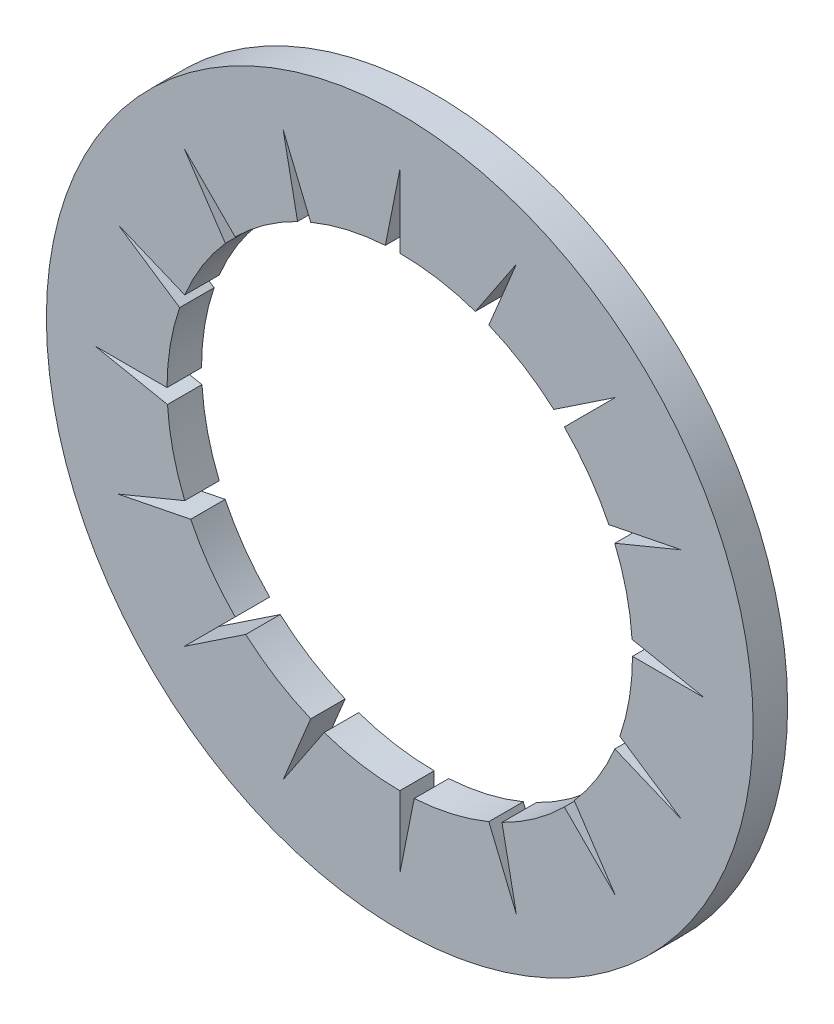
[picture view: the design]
ISO-10303-21;
HEADER;
FILE_DESCRIPTION(('STEP AP214'),'2;1');
FILE_NAME('part.step','',(''),(''),'','','');
FILE_SCHEMA(('AUTOMOTIVE_DESIGN { 1 0 10303 214 1 1 1 1 }'));
ENDSEC;
DATA;
#1=APPLICATION_CONTEXT('core data for automotive mechanical design processes');
#2=APPLICATION_PROTOCOL_DEFINITION('international standard','automotive_design',2000,#1);
#3=PRODUCT_CONTEXT('',#1,'mechanical');
#4=PRODUCT('Part','Part','',(#3));
#5=PRODUCT_RELATED_PRODUCT_CATEGORY('part','',(#4));
#6=PRODUCT_DEFINITION_FORMATION('','',#4);
#7=PRODUCT_DEFINITION_CONTEXT('part definition',#1,'design');
#8=PRODUCT_DEFINITION('design','',#6,#7);
#9=PRODUCT_DEFINITION_SHAPE('','',#8);
#10=(LENGTH_UNIT() NAMED_UNIT(*) SI_UNIT(.MILLI.,.METRE.));
#11=(NAMED_UNIT(*) PLANE_ANGLE_UNIT() SI_UNIT($,.RADIAN.));
#12=(NAMED_UNIT(*) SI_UNIT($,.STERADIAN.) SOLID_ANGLE_UNIT());
#13=UNCERTAINTY_MEASURE_WITH_UNIT(LENGTH_MEASURE(1.E-05),#10,'distance_accuracy_value','');
#14=(GEOMETRIC_REPRESENTATION_CONTEXT(3) GLOBAL_UNCERTAINTY_ASSIGNED_CONTEXT((#13)) GLOBAL_UNIT_ASSIGNED_CONTEXT((#10,
#11,#12)) REPRESENTATION_CONTEXT('',''));
#15=CARTESIAN_POINT('',(0.,0.,0.));
#16=DIRECTION('',(0.,0.,1.));
#17=DIRECTION('',(1.,0.,0.));
#18=AXIS2_PLACEMENT_3D('',#15,#16,#17);
#19=CARTESIAN_POINT('',(0.,0.,0.));
#20=DIRECTION('',(0.,0.,1.));
#21=DIRECTION('',(1.,0.,0.));
#22=AXIS2_PLACEMENT_3D('',#19,#20,#21);
#23=CYLINDRICAL_SURFACE('',#22,6.75);
#24=DIRECTION('',(0.,0.,1.));
#25=VECTOR('',#24,1.);
#26=CARTESIAN_POINT('',(-2.58311316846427,6.23618684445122,-1.));
#27=LINE('',#26,#25);
#28=CARTESIAN_POINT('',(-2.58311316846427,6.23618684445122,-1.));
#29=VERTEX_POINT('',#28);
#30=CARTESIAN_POINT('',(-2.58311316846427,6.23618684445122,0.));
#31=VERTEX_POINT('',#30);
#32=EDGE_CURVE('E371',#29,#31,#27,.T.);
#33=ORIENTED_EDGE('',*,*,#32,.F.);
#34=CARTESIAN_POINT('',(0.,0.,-1.));
#35=DIRECTION('',(0.,0.,1.));
#36=DIRECTION('',(1.,0.,0.));
#37=AXIS2_PLACEMENT_3D('',#34,#35,#36);
#38=CIRCLE('',#37,6.75);
#39=CARTESIAN_POINT('',(-0.418307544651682,6.73702596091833,-1.));
#40=VERTEX_POINT('',#39);
#41=EDGE_CURVE('E11',#40,#29,#38,.T.);
#42=ORIENTED_EDGE('',*,*,#41,.F.);
#43=DIRECTION('',(0.,0.,1.));
#44=VECTOR('',#43,1.);
#45=CARTESIAN_POINT('',(-0.418307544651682,6.73702596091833,-1.));
#46=LINE('',#45,#44);
#47=CARTESIAN_POINT('',(-0.418307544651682,6.73702596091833,0.));
#48=VERTEX_POINT('',#47);
#49=EDGE_CURVE('E651',#40,#48,#46,.T.);
#50=ORIENTED_EDGE('',*,*,#49,.T.);
#51=CARTESIAN_POINT('',(0.,0.,0.));
#52=DIRECTION('',(0.,0.,1.));
#53=DIRECTION('',(1.,0.,0.));
#54=AXIS2_PLACEMENT_3D('',#51,#52,#53);
#55=CIRCLE('',#54,6.75);
#56=EDGE_CURVE('E656',#48,#31,#55,.T.);
#57=ORIENTED_EDGE('',*,*,#56,.T.);
#58=EDGE_LOOP('',(#33,#42,#50,#57));
#59=FACE_BOUND('',#58,.T.);
#60=ADVANCED_FACE('F41',(#59),#23,.F.);
#61=DIRECTION('',(0.,0.,1.));
#62=VECTOR('',#61,1.);
#63=CARTESIAN_POINT('',(-2.9646139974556,6.06412102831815,-1.));
#64=LINE('',#63,#62);
#65=CARTESIAN_POINT('',(-2.9646139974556,6.06412102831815,-1.));
#66=VERTEX_POINT('',#65);
#67=CARTESIAN_POINT('',(-2.9646139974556,6.06412102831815,0.));
#68=VERTEX_POINT('',#67);
#69=EDGE_CURVE('E353',#66,#68,#64,.T.);
#70=ORIENTED_EDGE('',*,*,#69,.T.);
#71=CARTESIAN_POINT('',(-4.77297077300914,4.77297077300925,0.));
#72=VERTEX_POINT('',#71);
#73=EDGE_CURVE('E660',#68,#72,#55,.T.);
#74=ORIENTED_EDGE('',*,*,#73,.T.);
#75=DIRECTION('',(0.,0.,1.));
#76=VECTOR('',#75,1.);
#77=CARTESIAN_POINT('',(-4.77297077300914,4.77297077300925,-1.));
#78=LINE('',#77,#76);
#79=CARTESIAN_POINT('',(-4.77297077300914,4.77297077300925,-1.));
#80=VERTEX_POINT('',#79);
#81=EDGE_CURVE('E384',#80,#72,#78,.T.);
#82=ORIENTED_EDGE('',*,*,#81,.F.);
#83=EDGE_CURVE('E49',#66,#80,#38,.T.);
#84=ORIENTED_EDGE('',*,*,#83,.F.);
#85=EDGE_LOOP('',(#70,#74,#82,#84));
#86=FACE_BOUND('',#85,.T.);
#87=ADVANCED_FACE('F712',(#86),#23,.F.);
#88=DIRECTION('',(0.,0.,1.));
#89=VECTOR('',#88,1.);
#90=CARTESIAN_POINT('',(-5.05958484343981,4.46800864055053,-1.));
#91=LINE('',#90,#89);
#92=CARTESIAN_POINT('',(-5.05958484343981,4.46800864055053,-1.));
#93=VERTEX_POINT('',#92);
#94=CARTESIAN_POINT('',(-5.05958484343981,4.46800864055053,0.));
#95=VERTEX_POINT('',#94);
#96=EDGE_CURVE('E387',#93,#95,#91,.T.);
#97=ORIENTED_EDGE('',*,*,#96,.T.);
#98=CARTESIAN_POINT('',(-6.23618684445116,2.58311316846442,0.));
#99=VERTEX_POINT('',#98);
#100=EDGE_CURVE('E715',#95,#99,#55,.T.);
#101=ORIENTED_EDGE('',*,*,#100,.T.);
#102=DIRECTION('',(0.,0.,1.));
#103=VECTOR('',#102,1.);
#104=CARTESIAN_POINT('',(-6.23618684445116,2.58311316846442,-1.));
#105=LINE('',#104,#103);
#106=CARTESIAN_POINT('',(-6.23618684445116,2.58311316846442,-1.));
#107=VERTEX_POINT('',#106);
#108=EDGE_CURVE('E401',#107,#99,#105,.T.);
#109=ORIENTED_EDGE('',*,*,#108,.F.);
#110=EDGE_CURVE('E702',#93,#107,#38,.T.);
#111=ORIENTED_EDGE('',*,*,#110,.F.);
#112=EDGE_LOOP('',(#97,#101,#109,#111));
#113=FACE_BOUND('',#112,.T.);
#114=ADVANCED_FACE('F787',(#113),#23,.F.);
#115=DIRECTION('',(0.,0.,1.));
#116=VECTOR('',#115,1.);
#117=CARTESIAN_POINT('',(-6.38427976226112,2.19168243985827,-1.));
#118=LINE('',#117,#116);
#119=CARTESIAN_POINT('',(-6.38427976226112,2.19168243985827,-1.));
#120=VERTEX_POINT('',#119);
#121=CARTESIAN_POINT('',(-6.38427976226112,2.19168243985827,0.));
#122=VERTEX_POINT('',#121);
#123=EDGE_CURVE('E405',#120,#122,#118,.T.);
#124=ORIENTED_EDGE('',*,*,#123,.T.);
#125=CARTESIAN_POINT('',(-6.75,0.,0.));
#126=VERTEX_POINT('',#125);
#127=EDGE_CURVE('E716',#122,#126,#55,.T.);
#128=ORIENTED_EDGE('',*,*,#127,.T.);
#129=DIRECTION('',(0.,0.,1.));
#130=VECTOR('',#129,1.);
#131=CARTESIAN_POINT('',(-6.75,0.,-1.));
#132=LINE('',#131,#130);
#133=CARTESIAN_POINT('',(-6.75,0.,-1.));
#134=VERTEX_POINT('',#133);
#135=EDGE_CURVE('E420',#134,#126,#132,.T.);
#136=ORIENTED_EDGE('',*,*,#135,.F.);
#137=EDGE_CURVE('E699',#120,#134,#38,.T.);
#138=ORIENTED_EDGE('',*,*,#137,.F.);
#139=EDGE_LOOP('',(#124,#128,#136,#138));
#140=FACE_BOUND('',#139,.T.);
#141=ADVANCED_FACE('F927',(#140),#23,.F.);
#142=DIRECTION('',(0.,0.,1.));
#143=VECTOR('',#142,1.);
#144=CARTESIAN_POINT('',(-6.73702596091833,-0.418307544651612,-1.));
#145=LINE('',#144,#143);
#146=CARTESIAN_POINT('',(-6.73702596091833,-0.418307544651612,-1.));
#147=VERTEX_POINT('',#146);
#148=CARTESIAN_POINT('',(-6.73702596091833,-0.418307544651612,0.));
#149=VERTEX_POINT('',#148);
#150=EDGE_CURVE('E424',#147,#149,#145,.T.);
#151=ORIENTED_EDGE('',*,*,#150,.T.);
#152=CARTESIAN_POINT('',(-6.23618684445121,-2.58311316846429,0.));
#153=VERTEX_POINT('',#152);
#154=EDGE_CURVE('E720',#149,#153,#55,.T.);
#155=ORIENTED_EDGE('',*,*,#154,.T.);
#156=DIRECTION('',(0.,0.,1.));
#157=VECTOR('',#156,1.);
#158=CARTESIAN_POINT('',(-6.23618684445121,-2.58311316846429,-1.));
#159=LINE('',#158,#157);
#160=CARTESIAN_POINT('',(-6.23618684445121,-2.58311316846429,-1.));
#161=VERTEX_POINT('',#160);
#162=EDGE_CURVE('E439',#161,#153,#159,.T.);
#163=ORIENTED_EDGE('',*,*,#162,.F.);
#164=EDGE_CURVE('E696',#147,#161,#38,.T.);
#165=ORIENTED_EDGE('',*,*,#164,.F.);
#166=EDGE_LOOP('',(#151,#155,#163,#165));
#167=FACE_BOUND('',#166,.T.);
#168=ADVANCED_FACE('F919',(#167),#23,.F.);
#169=DIRECTION('',(0.,0.,1.));
#170=VECTOR('',#169,1.);
#171=CARTESIAN_POINT('',(-6.06412102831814,-2.96461399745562,-1.));
#172=LINE('',#171,#170);
#173=CARTESIAN_POINT('',(-6.06412102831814,-2.96461399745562,-1.));
#174=VERTEX_POINT('',#173);
#175=CARTESIAN_POINT('',(-6.06412102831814,-2.96461399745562,0.));
#176=VERTEX_POINT('',#175);
#177=EDGE_CURVE('E443',#174,#176,#172,.T.);
#178=ORIENTED_EDGE('',*,*,#177,.T.);
#179=CARTESIAN_POINT('',(-4.77297077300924,-4.77297077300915,0.));
#180=VERTEX_POINT('',#179);
#181=EDGE_CURVE('E724',#176,#180,#55,.T.);
#182=ORIENTED_EDGE('',*,*,#181,.T.);
#183=DIRECTION('',(0.,0.,1.));
#184=VECTOR('',#183,1.);
#185=CARTESIAN_POINT('',(-4.77297077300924,-4.77297077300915,-1.));
#186=LINE('',#185,#184);
#187=CARTESIAN_POINT('',(-4.77297077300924,-4.77297077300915,-1.));
#188=VERTEX_POINT('',#187);
#189=EDGE_CURVE('E458',#188,#180,#186,.T.);
#190=ORIENTED_EDGE('',*,*,#189,.F.);
#191=EDGE_CURVE('E693',#174,#188,#38,.T.);
#192=ORIENTED_EDGE('',*,*,#191,.F.);
#193=EDGE_LOOP('',(#178,#182,#190,#192));
#194=FACE_BOUND('',#193,.T.);
#195=ADVANCED_FACE('F912',(#194),#23,.F.);
#196=DIRECTION('',(0.,0.,1.));
#197=VECTOR('',#196,1.);
#198=CARTESIAN_POINT('',(-4.46800864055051,-5.05958484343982,-1.));
#199=LINE('',#198,#197);
#200=CARTESIAN_POINT('',(-4.46800864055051,-5.05958484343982,-1.));
#201=VERTEX_POINT('',#200);
#202=CARTESIAN_POINT('',(-4.46800864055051,-5.05958484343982,0.));
#203=VERTEX_POINT('',#202);
#204=EDGE_CURVE('E462',#201,#203,#199,.T.);
#205=ORIENTED_EDGE('',*,*,#204,.T.);
#206=CARTESIAN_POINT('',(-2.58311316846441,-6.23618684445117,0.));
#207=VERTEX_POINT('',#206);
#208=EDGE_CURVE('E728',#203,#207,#55,.T.);
#209=ORIENTED_EDGE('',*,*,#208,.T.);
#210=DIRECTION('',(0.,0.,1.));
#211=VECTOR('',#210,1.);
#212=CARTESIAN_POINT('',(-2.58311316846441,-6.23618684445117,-1.));
#213=LINE('',#212,#211);
#214=CARTESIAN_POINT('',(-2.58311316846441,-6.23618684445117,-1.));
#215=VERTEX_POINT('',#214);
#216=EDGE_CURVE('E477',#215,#207,#213,.T.);
#217=ORIENTED_EDGE('',*,*,#216,.F.);
#218=EDGE_CURVE('E690',#201,#215,#38,.T.);
#219=ORIENTED_EDGE('',*,*,#218,.F.);
#220=EDGE_LOOP('',(#205,#209,#217,#219));
#221=FACE_BOUND('',#220,.T.);
#222=ADVANCED_FACE('F904',(#221),#23,.F.);
#223=DIRECTION('',(0.,0.,1.));
#224=VECTOR('',#223,1.);
#225=CARTESIAN_POINT('',(-2.19168243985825,-6.38427976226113,-1.));
#226=LINE('',#225,#224);
#227=CARTESIAN_POINT('',(-2.19168243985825,-6.38427976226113,-1.));
#228=VERTEX_POINT('',#227);
#229=CARTESIAN_POINT('',(-2.19168243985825,-6.38427976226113,0.));
#230=VERTEX_POINT('',#229);
#231=EDGE_CURVE('E481',#228,#230,#226,.T.);
#232=ORIENTED_EDGE('',*,*,#231,.T.);
#233=CARTESIAN_POINT('',(0.,-6.75,0.));
#234=VERTEX_POINT('',#233);
#235=EDGE_CURVE('E732',#230,#234,#55,.T.);
#236=ORIENTED_EDGE('',*,*,#235,.T.);
#237=DIRECTION('',(0.,0.,1.));
#238=VECTOR('',#237,1.);
#239=CARTESIAN_POINT('',(0.,-6.75,-1.));
#240=LINE('',#239,#238);
#241=CARTESIAN_POINT('',(0.,-6.75,-1.));
#242=VERTEX_POINT('',#241);
#243=EDGE_CURVE('E496',#242,#234,#240,.T.);
#244=ORIENTED_EDGE('',*,*,#243,.F.);
#245=EDGE_CURVE('E687',#228,#242,#38,.T.);
#246=ORIENTED_EDGE('',*,*,#245,.F.);
#247=EDGE_LOOP('',(#232,#236,#244,#246));
#248=FACE_BOUND('',#247,.T.);
#249=ADVANCED_FACE('F897',(#248),#23,.F.);
#250=DIRECTION('',(0.,0.,1.));
#251=VECTOR('',#250,1.);
#252=CARTESIAN_POINT('',(0.418307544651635,-6.73702596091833,-1.));
#253=LINE('',#252,#251);
#254=CARTESIAN_POINT('',(0.418307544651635,-6.73702596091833,-1.));
#255=VERTEX_POINT('',#254);
#256=CARTESIAN_POINT('',(0.418307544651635,-6.73702596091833,0.));
#257=VERTEX_POINT('',#256);
#258=EDGE_CURVE('E500',#255,#257,#253,.T.);
#259=ORIENTED_EDGE('',*,*,#258,.T.);
#260=CARTESIAN_POINT('',(2.58311316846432,-6.2361868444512,0.));
#261=VERTEX_POINT('',#260);
#262=EDGE_CURVE('E736',#257,#261,#55,.T.);
#263=ORIENTED_EDGE('',*,*,#262,.T.);
#264=DIRECTION('',(0.,0.,1.));
#265=VECTOR('',#264,1.);
#266=CARTESIAN_POINT('',(2.58311316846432,-6.2361868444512,-1.));
#267=LINE('',#266,#265);
#268=CARTESIAN_POINT('',(2.58311316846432,-6.2361868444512,-1.));
#269=VERTEX_POINT('',#268);
#270=EDGE_CURVE('E515',#269,#261,#267,.T.);
#271=ORIENTED_EDGE('',*,*,#270,.F.);
#272=EDGE_CURVE('E684',#255,#269,#38,.T.);
#273=ORIENTED_EDGE('',*,*,#272,.F.);
#274=EDGE_LOOP('',(#259,#263,#271,#273));
#275=FACE_BOUND('',#274,.T.);
#276=ADVANCED_FACE('F889',(#275),#23,.F.);
#277=DIRECTION('',(0.,0.,1.));
#278=VECTOR('',#277,1.);
#279=CARTESIAN_POINT('',(2.96461399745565,-6.06412102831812,-1.));
#280=LINE('',#279,#278);
#281=CARTESIAN_POINT('',(2.96461399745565,-6.06412102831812,-1.));
#282=VERTEX_POINT('',#281);
#283=CARTESIAN_POINT('',(2.96461399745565,-6.06412102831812,0.));
#284=VERTEX_POINT('',#283);
#285=EDGE_CURVE('E519',#282,#284,#280,.T.);
#286=ORIENTED_EDGE('',*,*,#285,.T.);
#287=CARTESIAN_POINT('',(4.77297077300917,-4.77297077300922,0.));
#288=VERTEX_POINT('',#287);
#289=EDGE_CURVE('E740',#284,#288,#55,.T.);
#290=ORIENTED_EDGE('',*,*,#289,.T.);
#291=DIRECTION('',(0.,0.,1.));
#292=VECTOR('',#291,1.);
#293=CARTESIAN_POINT('',(4.77297077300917,-4.77297077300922,-1.));
#294=LINE('',#293,#292);
#295=CARTESIAN_POINT('',(4.77297077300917,-4.77297077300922,-1.));
#296=VERTEX_POINT('',#295);
#297=EDGE_CURVE('E534',#296,#288,#294,.T.);
#298=ORIENTED_EDGE('',*,*,#297,.F.);
#299=EDGE_CURVE('E681',#282,#296,#38,.T.);
#300=ORIENTED_EDGE('',*,*,#299,.F.);
#301=EDGE_LOOP('',(#286,#290,#298,#300));
#302=FACE_BOUND('',#301,.T.);
#303=ADVANCED_FACE('F882',(#302),#23,.F.);
#304=DIRECTION('',(0.,0.,1.));
#305=VECTOR('',#304,1.);
#306=CARTESIAN_POINT('',(5.05958484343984,-4.46800864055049,-1.));
#307=LINE('',#306,#305);
#308=CARTESIAN_POINT('',(5.05958484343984,-4.46800864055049,-1.));
#309=VERTEX_POINT('',#308);
#310=CARTESIAN_POINT('',(5.05958484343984,-4.46800864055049,0.));
#311=VERTEX_POINT('',#310);
#312=EDGE_CURVE('E538',#309,#311,#307,.T.);
#313=ORIENTED_EDGE('',*,*,#312,.T.);
#314=CARTESIAN_POINT('',(6.23618684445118,-2.58311316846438,0.));
#315=VERTEX_POINT('',#314);
#316=EDGE_CURVE('E744',#311,#315,#55,.T.);
#317=ORIENTED_EDGE('',*,*,#316,.T.);
#318=DIRECTION('',(0.,0.,1.));
#319=VECTOR('',#318,1.);
#320=CARTESIAN_POINT('',(6.23618684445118,-2.58311316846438,-1.));
#321=LINE('',#320,#319);
#322=CARTESIAN_POINT('',(6.23618684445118,-2.58311316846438,-1.));
#323=VERTEX_POINT('',#322);
#324=EDGE_CURVE('E553',#323,#315,#321,.T.);
#325=ORIENTED_EDGE('',*,*,#324,.F.);
#326=EDGE_CURVE('E678',#309,#323,#38,.T.);
#327=ORIENTED_EDGE('',*,*,#326,.F.);
#328=EDGE_LOOP('',(#313,#317,#325,#327));
#329=FACE_BOUND('',#328,.T.);
#330=ADVANCED_FACE('F874',(#329),#23,.F.);
#331=DIRECTION('',(0.,0.,1.));
#332=VECTOR('',#331,1.);
#333=CARTESIAN_POINT('',(6.38427976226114,-2.19168243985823,-1.));
#334=LINE('',#333,#332);
#335=CARTESIAN_POINT('',(6.38427976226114,-2.19168243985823,-1.));
#336=VERTEX_POINT('',#335);
#337=CARTESIAN_POINT('',(6.38427976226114,-2.19168243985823,0.));
#338=VERTEX_POINT('',#337);
#339=EDGE_CURVE('E557',#336,#338,#334,.T.);
#340=ORIENTED_EDGE('',*,*,#339,.T.);
#341=CARTESIAN_POINT('',(6.75,0.,0.));
#342=VERTEX_POINT('',#341);
#343=EDGE_CURVE('E748',#338,#342,#55,.T.);
#344=ORIENTED_EDGE('',*,*,#343,.T.);
#345=DIRECTION('',(0.,0.,1.));
#346=VECTOR('',#345,1.);
#347=CARTESIAN_POINT('',(6.75,0.,-1.));
#348=LINE('',#347,#346);
#349=CARTESIAN_POINT('',(6.75,0.,-1.));
#350=VERTEX_POINT('',#349);
#351=EDGE_CURVE('E572',#350,#342,#348,.T.);
#352=ORIENTED_EDGE('',*,*,#351,.F.);
#353=EDGE_CURVE('E675',#336,#350,#38,.T.);
#354=ORIENTED_EDGE('',*,*,#353,.F.);
#355=EDGE_LOOP('',(#340,#344,#352,#354));
#356=FACE_BOUND('',#355,.T.);
#357=ADVANCED_FACE('F867',(#356),#23,.F.);
#358=DIRECTION('',(0.,0.,1.));
#359=VECTOR('',#358,1.);
#360=CARTESIAN_POINT('',(6.73702596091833,0.418307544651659,-1.));
#361=LINE('',#360,#359);
#362=CARTESIAN_POINT('',(6.73702596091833,0.418307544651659,-1.));
#363=VERTEX_POINT('',#362);
#364=CARTESIAN_POINT('',(6.73702596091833,0.418307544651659,0.));
#365=VERTEX_POINT('',#364);
#366=EDGE_CURVE('E576',#363,#365,#361,.T.);
#367=ORIENTED_EDGE('',*,*,#366,.T.);
#368=CARTESIAN_POINT('',(6.23618684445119,2.58311316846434,0.));
#369=VERTEX_POINT('',#368);
#370=EDGE_CURVE('E752',#365,#369,#55,.T.);
#371=ORIENTED_EDGE('',*,*,#370,.T.);
#372=DIRECTION('',(0.,0.,1.));
#373=VECTOR('',#372,1.);
#374=CARTESIAN_POINT('',(6.23618684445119,2.58311316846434,-1.));
#375=LINE('',#374,#373);
#376=CARTESIAN_POINT('',(6.23618684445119,2.58311316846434,-1.));
#377=VERTEX_POINT('',#376);
#378=EDGE_CURVE('E591',#377,#369,#375,.T.);
#379=ORIENTED_EDGE('',*,*,#378,.F.);
#380=EDGE_CURVE('E672',#363,#377,#38,.T.);
#381=ORIENTED_EDGE('',*,*,#380,.F.);
#382=EDGE_LOOP('',(#367,#371,#379,#381));
#383=FACE_BOUND('',#382,.T.);
#384=ADVANCED_FACE('F799',(#383),#23,.F.);
#385=DIRECTION('',(0.,0.,1.));
#386=VECTOR('',#385,1.);
#387=CARTESIAN_POINT('',(6.06412102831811,2.96461399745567,-1.));
#388=LINE('',#387,#386);
#389=CARTESIAN_POINT('',(6.06412102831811,2.96461399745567,-1.));
#390=VERTEX_POINT('',#389);
#391=CARTESIAN_POINT('',(6.06412102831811,2.96461399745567,0.));
#392=VERTEX_POINT('',#391);
#393=EDGE_CURVE('E595',#390,#392,#388,.T.);
#394=ORIENTED_EDGE('',*,*,#393,.T.);
#395=CARTESIAN_POINT('',(4.77297077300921,4.77297077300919,0.));
#396=VERTEX_POINT('',#395);
#397=EDGE_CURVE('E756',#392,#396,#55,.T.);
#398=ORIENTED_EDGE('',*,*,#397,.T.);
#399=DIRECTION('',(0.,0.,1.));
#400=VECTOR('',#399,1.);
#401=CARTESIAN_POINT('',(4.77297077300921,4.77297077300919,-1.));
#402=LINE('',#401,#400);
#403=CARTESIAN_POINT('',(4.77297077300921,4.77297077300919,-1.));
#404=VERTEX_POINT('',#403);
#405=EDGE_CURVE('E610',#404,#396,#402,.T.);
#406=ORIENTED_EDGE('',*,*,#405,.F.);
#407=EDGE_CURVE('E669',#390,#404,#38,.T.);
#408=ORIENTED_EDGE('',*,*,#407,.F.);
#409=EDGE_LOOP('',(#394,#398,#406,#408));
#410=FACE_BOUND('',#409,.T.);
#411=ADVANCED_FACE('F795',(#410),#23,.F.);
#412=DIRECTION('',(0.,0.,1.));
#413=VECTOR('',#412,1.);
#414=CARTESIAN_POINT('',(4.46800864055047,5.05958484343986,-1.));
#415=LINE('',#414,#413);
#416=CARTESIAN_POINT('',(4.46800864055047,5.05958484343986,-1.));
#417=VERTEX_POINT('',#416);
#418=CARTESIAN_POINT('',(4.46800864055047,5.05958484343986,0.));
#419=VERTEX_POINT('',#418);
#420=EDGE_CURVE('E614',#417,#419,#415,.T.);
#421=ORIENTED_EDGE('',*,*,#420,.T.);
#422=CARTESIAN_POINT('',(2.58311316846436,6.23618684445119,0.));
#423=VERTEX_POINT('',#422);
#424=EDGE_CURVE('E760',#419,#423,#55,.T.);
#425=ORIENTED_EDGE('',*,*,#424,.T.);
#426=DIRECTION('',(0.,0.,1.));
#427=VECTOR('',#426,1.);
#428=CARTESIAN_POINT('',(2.58311316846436,6.23618684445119,-1.));
#429=LINE('',#428,#427);
#430=CARTESIAN_POINT('',(2.58311316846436,6.23618684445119,-1.));
#431=VERTEX_POINT('',#430);
#432=EDGE_CURVE('E629',#431,#423,#429,.T.);
#433=ORIENTED_EDGE('',*,*,#432,.F.);
#434=EDGE_CURVE('E666',#417,#431,#38,.T.);
#435=ORIENTED_EDGE('',*,*,#434,.F.);
#436=EDGE_LOOP('',(#421,#425,#433,#435));
#437=FACE_BOUND('',#436,.T.);
#438=ADVANCED_FACE('F789',(#437),#23,.F.);
#439=DIRECTION('',(0.,0.,1.));
#440=VECTOR('',#439,1.);
#441=CARTESIAN_POINT('',(2.19168243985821,6.38427976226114,-1.));
#442=LINE('',#441,#440);
#443=CARTESIAN_POINT('',(2.19168243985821,6.38427976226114,-1.));
#444=VERTEX_POINT('',#443);
#445=CARTESIAN_POINT('',(2.19168243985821,6.38427976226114,0.));
#446=VERTEX_POINT('',#445);
#447=EDGE_CURVE('E633',#444,#446,#442,.T.);
#448=ORIENTED_EDGE('',*,*,#447,.T.);
#449=CARTESIAN_POINT('',(0.,6.75,0.));
#450=VERTEX_POINT('',#449);
#451=EDGE_CURVE('E650',#446,#450,#55,.T.);
#452=ORIENTED_EDGE('',*,*,#451,.T.);
#453=DIRECTION('',(0.,0.,1.));
#454=VECTOR('',#453,1.);
#455=CARTESIAN_POINT('',(0.,6.75,-1.));
#456=LINE('',#455,#454);
#457=CARTESIAN_POINT('',(0.,6.75,-1.));
#458=VERTEX_POINT('',#457);
#459=EDGE_CURVE('E647',#458,#450,#456,.T.);
#460=ORIENTED_EDGE('',*,*,#459,.F.);
#461=EDGE_CURVE('E50',#444,#458,#38,.T.);
#462=ORIENTED_EDGE('',*,*,#461,.F.);
#463=EDGE_LOOP('',(#448,#452,#460,#462));
#464=FACE_BOUND('',#463,.T.);
#465=ADVANCED_FACE('F43',(#464),#23,.F.);
#466=CARTESIAN_POINT('',(6.75,0.,-1.));
#467=DIRECTION('',(0.,0.,-1.));
#468=DIRECTION('',(-1.,0.,0.));
#469=AXIS2_PLACEMENT_3D('',#466,#467,#468);
#470=PLANE('',#469);
#471=DIRECTION('',(-0.382683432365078,0.923879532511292,0.));
#472=VECTOR('',#471,1.);
#473=CARTESIAN_POINT('',(-2.58311316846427,6.23618684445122,-1.));
#474=LINE('',#473,#472);
#475=CARTESIAN_POINT('',(-3.38292154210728,8.16709506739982,-1.));
#476=VERTEX_POINT('',#475);
#477=EDGE_CURVE('E349',#29,#476,#474,.T.);
#478=ORIENTED_EDGE('',*,*,#477,.T.);
#479=DIRECTION('',(0.195090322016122,-0.980785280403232,0.));
#480=VECTOR('',#479,1.);
#481=CARTESIAN_POINT('',(-3.38292154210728,8.16709506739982,-1.));
#482=LINE('',#481,#480);
#483=EDGE_CURVE('E354',#476,#66,#482,.T.);
#484=ORIENTED_EDGE('',*,*,#483,.T.);
#485=ORIENTED_EDGE('',*,*,#83,.T.);
#486=DIRECTION('',(-0.707106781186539,0.707106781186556,0.));
#487=VECTOR('',#486,1.);
#488=CARTESIAN_POINT('',(-4.77297077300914,4.77297077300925,-1.));
#489=LINE('',#488,#487);
#490=CARTESIAN_POINT('',(-6.250823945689,6.25082394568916,-1.));
#491=VERTEX_POINT('',#490);
#492=EDGE_CURVE('E374',#80,#491,#489,.T.);
#493=ORIENTED_EDGE('',*,*,#492,.T.);
#494=DIRECTION('',(0.555570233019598,-0.831469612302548,0.));
#495=VECTOR('',#494,1.);
#496=CARTESIAN_POINT('',(-6.250823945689,6.25082394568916,-1.));
#497=LINE('',#496,#495);
#498=EDGE_CURVE('E377',#491,#93,#497,.T.);
#499=ORIENTED_EDGE('',*,*,#498,.T.);
#500=ORIENTED_EDGE('',*,*,#110,.T.);
#501=DIRECTION('',(-0.923879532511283,0.3826834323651,0.));
#502=VECTOR('',#501,1.);
#503=CARTESIAN_POINT('',(-6.23618684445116,2.58311316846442,-1.));
#504=LINE('',#503,#502);
#505=CARTESIAN_POINT('',(-8.16709506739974,3.38292154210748,-1.));
#506=VERTEX_POINT('',#505);
#507=EDGE_CURVE('E391',#107,#506,#504,.T.);
#508=ORIENTED_EDGE('',*,*,#507,.T.);
#509=DIRECTION('',(0.831469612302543,-0.555570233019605,0.));
#510=VECTOR('',#509,1.);
#511=CARTESIAN_POINT('',(-8.16709506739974,3.38292154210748,-1.));
#512=LINE('',#511,#510);
#513=EDGE_CURVE('E394',#506,#120,#512,.T.);
#514=ORIENTED_EDGE('',*,*,#513,.T.);
#515=ORIENTED_EDGE('',*,*,#137,.T.);
#516=DIRECTION('',(-1.,0.,0.));
#517=VECTOR('',#516,1.);
#518=CARTESIAN_POINT('',(-6.75,0.,-1.));
#519=LINE('',#518,#517);
#520=CARTESIAN_POINT('',(-8.84,0.,-1.));
#521=VERTEX_POINT('',#520);
#522=EDGE_CURVE('E410',#134,#521,#519,.T.);
#523=ORIENTED_EDGE('',*,*,#522,.T.);
#524=DIRECTION('',(0.98078528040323,-0.195090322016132,0.));
#525=VECTOR('',#524,1.);
#526=CARTESIAN_POINT('',(-8.84,0.,-1.));
#527=LINE('',#526,#525);
#528=EDGE_CURVE('E413',#521,#147,#527,.T.);
#529=ORIENTED_EDGE('',*,*,#528,.T.);
#530=ORIENTED_EDGE('',*,*,#164,.T.);
#531=DIRECTION('',(-0.923879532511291,-0.382683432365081,0.));
#532=VECTOR('',#531,1.);
#533=CARTESIAN_POINT('',(-6.23618684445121,-2.58311316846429,-1.));
#534=LINE('',#533,#532);
#535=CARTESIAN_POINT('',(-8.16709506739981,-3.38292154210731,-1.));
#536=VERTEX_POINT('',#535);
#537=EDGE_CURVE('E429',#161,#536,#534,.T.);
#538=ORIENTED_EDGE('',*,*,#537,.T.);
#539=DIRECTION('',(0.980785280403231,0.195090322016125,0.));
#540=VECTOR('',#539,1.);
#541=CARTESIAN_POINT('',(-8.16709506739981,-3.38292154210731,-1.));
#542=LINE('',#541,#540);
#543=EDGE_CURVE('E432',#536,#174,#542,.T.);
#544=ORIENTED_EDGE('',*,*,#543,.T.);
#545=ORIENTED_EDGE('',*,*,#191,.T.);
#546=DIRECTION('',(-0.707106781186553,-0.707106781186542,0.));
#547=VECTOR('',#546,1.);
#548=CARTESIAN_POINT('',(-4.77297077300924,-4.77297077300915,-1.));
#549=LINE('',#548,#547);
#550=CARTESIAN_POINT('',(-6.25082394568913,-6.25082394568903,-1.));
#551=VERTEX_POINT('',#550);
#552=EDGE_CURVE('E448',#188,#551,#549,.T.);
#553=ORIENTED_EDGE('',*,*,#552,.T.);
#554=DIRECTION('',(0.831469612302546,0.555570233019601,0.));
#555=VECTOR('',#554,1.);
#556=CARTESIAN_POINT('',(-6.25082394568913,-6.25082394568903,-1.));
#557=LINE('',#556,#555);
#558=EDGE_CURVE('E451',#551,#201,#557,.T.);
#559=ORIENTED_EDGE('',*,*,#558,.T.);
#560=ORIENTED_EDGE('',*,*,#218,.T.);
#561=DIRECTION('',(-0.382683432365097,-0.923879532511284,0.));
#562=VECTOR('',#561,1.);
#563=CARTESIAN_POINT('',(-2.58311316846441,-6.23618684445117,-1.));
#564=LINE('',#563,#562);
#565=CARTESIAN_POINT('',(-3.38292154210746,-8.16709506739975,-1.));
#566=VERTEX_POINT('',#565);
#567=EDGE_CURVE('E467',#215,#566,#564,.T.);
#568=ORIENTED_EDGE('',*,*,#567,.T.);
#569=DIRECTION('',(0.555570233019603,0.831469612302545,0.));
#570=VECTOR('',#569,1.);
#571=CARTESIAN_POINT('',(-3.38292154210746,-8.16709506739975,-1.));
#572=LINE('',#571,#570);
#573=EDGE_CURVE('E470',#566,#228,#572,.T.);
#574=ORIENTED_EDGE('',*,*,#573,.T.);
#575=ORIENTED_EDGE('',*,*,#245,.T.);
#576=DIRECTION('',(0.,-1.,0.));
#577=VECTOR('',#576,1.);
#578=CARTESIAN_POINT('',(0.,-6.75,-1.));
#579=LINE('',#578,#577);
#580=CARTESIAN_POINT('',(0.,-8.84,-1.));
#581=VERTEX_POINT('',#580);
#582=EDGE_CURVE('E486',#242,#581,#579,.T.);
#583=ORIENTED_EDGE('',*,*,#582,.T.);
#584=DIRECTION('',(0.195090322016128,0.98078528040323,0.));
#585=VECTOR('',#584,1.);
#586=CARTESIAN_POINT('',(0.,-8.84,-1.));
#587=LINE('',#586,#585);
#588=EDGE_CURVE('E489',#581,#255,#587,.T.);
#589=ORIENTED_EDGE('',*,*,#588,.T.);
#590=ORIENTED_EDGE('',*,*,#272,.T.);
#591=DIRECTION('',(0.382683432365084,-0.923879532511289,0.));
#592=VECTOR('',#591,1.);
#593=CARTESIAN_POINT('',(2.58311316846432,-6.2361868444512,-1.));
#594=LINE('',#593,#592);
#595=CARTESIAN_POINT('',(3.38292154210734,-8.1670950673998,-1.));
#596=VERTEX_POINT('',#595);
#597=EDGE_CURVE('E505',#269,#596,#594,.T.);
#598=ORIENTED_EDGE('',*,*,#597,.T.);
#599=DIRECTION('',(-0.195090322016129,0.98078528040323,0.));
#600=VECTOR('',#599,1.);
#601=CARTESIAN_POINT('',(3.38292154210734,-8.1670950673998,-1.));
#602=LINE('',#601,#600);
#603=EDGE_CURVE('E508',#596,#282,#602,.T.);
#604=ORIENTED_EDGE('',*,*,#603,.T.);
#605=ORIENTED_EDGE('',*,*,#299,.T.);
#606=DIRECTION('',(0.707106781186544,-0.707106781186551,0.));
#607=VECTOR('',#606,1.);
#608=CARTESIAN_POINT('',(4.77297077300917,-4.77297077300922,-1.));
#609=LINE('',#608,#607);
#610=CARTESIAN_POINT('',(6.25082394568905,-6.25082394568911,-1.));
#611=VERTEX_POINT('',#610);
#612=EDGE_CURVE('E524',#296,#611,#609,.T.);
#613=ORIENTED_EDGE('',*,*,#612,.T.);
#614=DIRECTION('',(-0.555570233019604,0.831469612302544,0.));
#615=VECTOR('',#614,1.);
#616=CARTESIAN_POINT('',(6.25082394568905,-6.25082394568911,-1.));
#617=LINE('',#616,#615);
#618=EDGE_CURVE('E527',#611,#309,#617,.T.);
#619=ORIENTED_EDGE('',*,*,#618,.T.);
#620=ORIENTED_EDGE('',*,*,#326,.T.);
#621=DIRECTION('',(0.923879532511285,-0.382683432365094,0.));
#622=VECTOR('',#621,1.);
#623=CARTESIAN_POINT('',(6.23618684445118,-2.58311316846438,-1.));
#624=LINE('',#623,#622);
#625=CARTESIAN_POINT('',(8.16709506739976,-3.38292154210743,-1.));
#626=VERTEX_POINT('',#625);
#627=EDGE_CURVE('E543',#323,#626,#624,.T.);
#628=ORIENTED_EDGE('',*,*,#627,.T.);
#629=DIRECTION('',(-0.831469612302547,0.5555702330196,0.));
#630=VECTOR('',#629,1.);
#631=CARTESIAN_POINT('',(8.16709506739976,-3.38292154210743,-1.));
#632=LINE('',#631,#630);
#633=EDGE_CURVE('E546',#626,#336,#632,.T.);
#634=ORIENTED_EDGE('',*,*,#633,.T.);
#635=ORIENTED_EDGE('',*,*,#353,.T.);
#636=DIRECTION('',(1.,0.,0.));
#637=VECTOR('',#636,1.);
#638=CARTESIAN_POINT('',(6.75,0.,-1.));
#639=LINE('',#638,#637);
#640=CARTESIAN_POINT('',(8.84,0.,-1.));
#641=VERTEX_POINT('',#640);
#642=EDGE_CURVE('E562',#350,#641,#639,.T.);
#643=ORIENTED_EDGE('',*,*,#642,.T.);
#644=DIRECTION('',(-0.980785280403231,0.195090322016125,0.));
#645=VECTOR('',#644,1.);
#646=CARTESIAN_POINT('',(8.84,0.,-1.));
#647=LINE('',#646,#645);
#648=EDGE_CURVE('E565',#641,#363,#647,.T.);
#649=ORIENTED_EDGE('',*,*,#648,.T.);
#650=ORIENTED_EDGE('',*,*,#380,.T.);
#651=DIRECTION('',(0.923879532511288,0.382683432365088,0.));
#652=VECTOR('',#651,1.);
#653=CARTESIAN_POINT('',(6.23618684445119,2.58311316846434,-1.));
#654=LINE('',#653,#652);
#655=CARTESIAN_POINT('',(8.16709506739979,3.38292154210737,-1.));
#656=VERTEX_POINT('',#655);
#657=EDGE_CURVE('E581',#377,#656,#654,.T.);
#658=ORIENTED_EDGE('',*,*,#657,.T.);
#659=DIRECTION('',(-0.980785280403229,-0.195090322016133,0.));
#660=VECTOR('',#659,1.);
#661=CARTESIAN_POINT('',(8.16709506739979,3.38292154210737,-1.));
#662=LINE('',#661,#660);
#663=EDGE_CURVE('E584',#656,#390,#662,.T.);
#664=ORIENTED_EDGE('',*,*,#663,.T.);
#665=ORIENTED_EDGE('',*,*,#407,.T.);
#666=DIRECTION('',(0.707106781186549,0.707106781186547,0.));
#667=VECTOR('',#666,1.);
#668=CARTESIAN_POINT('',(4.7729707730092,4.77297077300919,-1.));
#669=LINE('',#668,#667);
#670=CARTESIAN_POINT('',(6.25082394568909,6.25082394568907,-1.));
#671=VERTEX_POINT('',#670);
#672=EDGE_CURVE('E600',#404,#671,#669,.T.);
#673=ORIENTED_EDGE('',*,*,#672,.T.);
#674=DIRECTION('',(-0.831469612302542,-0.555570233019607,0.));
#675=VECTOR('',#674,1.);
#676=CARTESIAN_POINT('',(6.25082394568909,6.25082394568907,-1.));
#677=LINE('',#676,#675);
#678=EDGE_CURVE('E603',#671,#417,#677,.T.);
#679=ORIENTED_EDGE('',*,*,#678,.T.);
#680=ORIENTED_EDGE('',*,*,#434,.T.);
#681=DIRECTION('',(0.38268343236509,0.923879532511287,0.));
#682=VECTOR('',#681,1.);
#683=CARTESIAN_POINT('',(2.58311316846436,6.23618684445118,-1.));
#684=LINE('',#683,#682);
#685=CARTESIAN_POINT('',(3.3829215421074,8.16709506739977,-1.));
#686=VERTEX_POINT('',#685);
#687=EDGE_CURVE('E619',#431,#686,#684,.T.);
#688=ORIENTED_EDGE('',*,*,#687,.T.);
#689=DIRECTION('',(-0.555570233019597,-0.831469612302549,0.));
#690=VECTOR('',#689,1.);
#691=CARTESIAN_POINT('',(3.3829215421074,8.16709506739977,-1.));
#692=LINE('',#691,#690);
#693=EDGE_CURVE('E622',#686,#444,#692,.T.);
#694=ORIENTED_EDGE('',*,*,#693,.T.);
#695=ORIENTED_EDGE('',*,*,#461,.T.);
#696=DIRECTION('',(0.,1.,0.));
#697=VECTOR('',#696,1.);
#698=CARTESIAN_POINT('',(0.,6.75,-1.));
#699=LINE('',#698,#697);
#700=CARTESIAN_POINT('',(0.,8.84,-1.));
#701=VERTEX_POINT('',#700);
#702=EDGE_CURVE('E638',#458,#701,#699,.T.);
#703=ORIENTED_EDGE('',*,*,#702,.T.);
#704=DIRECTION('',(-0.195090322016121,-0.980785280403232,0.));
#705=VECTOR('',#704,1.);
#706=CARTESIAN_POINT('',(0.,8.84,-1.));
#707=LINE('',#706,#705);
#708=EDGE_CURVE('E641',#701,#40,#707,.T.);
#709=ORIENTED_EDGE('',*,*,#708,.T.);
#710=ORIENTED_EDGE('',*,*,#41,.T.);
#711=EDGE_LOOP('',(#478,#484,#485,#493,#499,#500,#508,#514,#515,#523,#529,#530,#538,#544,#545,
#553,#559,#560,#568,#574,#575,#583,#589,#590,#598,#604,#605,#613,#619,#620,#628,#634,#635,#643,
#649,#650,#658,#664,#665,#673,#679,#680,#688,#694,#695,#703,#709,#710));
#712=FACE_BOUND('',#711,.T.);
#713=CARTESIAN_POINT('',(0.,0.,-1.));
#714=DIRECTION('',(0.,0.,1.));
#715=DIRECTION('',(1.,0.,0.));
#716=AXIS2_PLACEMENT_3D('',#713,#714,#715);
#717=CIRCLE('',#716,10.25);
#718=CARTESIAN_POINT('',(10.25,0.,-1.));
#719=VERTEX_POINT('',#718);
#720=EDGE_CURVE('E662',#719,#719,#717,.T.);
#721=ORIENTED_EDGE('',*,*,#720,.F.);
#722=EDGE_LOOP('',(#721));
#723=FACE_BOUND('',#722,.T.);
#724=ADVANCED_FACE('F362',(#712,#723),#470,.T.);
#725=CARTESIAN_POINT('',(0.,0.,0.));
#726=DIRECTION('',(0.,0.,1.));
#727=DIRECTION('',(1.,0.,0.));
#728=AXIS2_PLACEMENT_3D('',#725,#726,#727);
#729=CYLINDRICAL_SURFACE('',#728,10.25);
#730=ORIENTED_EDGE('',*,*,#720,.T.);
#731=EDGE_LOOP('',(#730));
#732=FACE_BOUND('',#731,.T.);
#733=CARTESIAN_POINT('',(0.,0.,0.));
#734=DIRECTION('',(0.,0.,1.));
#735=DIRECTION('',(1.,0.,0.));
#736=AXIS2_PLACEMENT_3D('',#733,#734,#735);
#737=CIRCLE('',#736,10.25);
#738=CARTESIAN_POINT('',(10.25,0.,0.));
#739=VERTEX_POINT('',#738);
#740=EDGE_CURVE('E659',#739,#739,#737,.T.);
#741=ORIENTED_EDGE('',*,*,#740,.F.);
#742=EDGE_LOOP('',(#741));
#743=FACE_BOUND('',#742,.T.);
#744=ADVANCED_FACE('F794',(#732,#743),#729,.T.);
#745=CARTESIAN_POINT('',(6.75,0.,0.));
#746=DIRECTION('',(0.,0.,1.));
#747=DIRECTION('',(1.,0.,0.));
#748=AXIS2_PLACEMENT_3D('',#745,#746,#747);
#749=PLANE('',#748);
#750=DIRECTION('',(-0.382683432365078,0.923879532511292,0.));
#751=VECTOR('',#750,1.);
#752=CARTESIAN_POINT('',(-2.58311316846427,6.23618684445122,0.));
#753=LINE('',#752,#751);
#754=CARTESIAN_POINT('',(-3.38292154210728,8.16709506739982,0.));
#755=VERTEX_POINT('',#754);
#756=EDGE_CURVE('E57',#31,#755,#753,.T.);
#757=ORIENTED_EDGE('',*,*,#756,.F.);
#758=ORIENTED_EDGE('',*,*,#56,.F.);
#759=DIRECTION('',(-0.195090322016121,-0.980785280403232,0.));
#760=VECTOR('',#759,1.);
#761=CARTESIAN_POINT('',(0.,8.84,0.));
#762=LINE('',#761,#760);
#763=CARTESIAN_POINT('',(0.,8.84,0.));
#764=VERTEX_POINT('',#763);
#765=EDGE_CURVE('E642',#764,#48,#762,.T.);
#766=ORIENTED_EDGE('',*,*,#765,.F.);
#767=DIRECTION('',(0.,1.,0.));
#768=VECTOR('',#767,1.);
#769=CARTESIAN_POINT('',(0.,6.75,0.));
#770=LINE('',#769,#768);
#771=EDGE_CURVE('E632',#450,#764,#770,.T.);
#772=ORIENTED_EDGE('',*,*,#771,.F.);
#773=ORIENTED_EDGE('',*,*,#451,.F.);
#774=DIRECTION('',(-0.555570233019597,-0.831469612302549,0.));
#775=VECTOR('',#774,1.);
#776=CARTESIAN_POINT('',(3.3829215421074,8.16709506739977,0.));
#777=LINE('',#776,#775);
#778=CARTESIAN_POINT('',(3.3829215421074,8.16709506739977,0.));
#779=VERTEX_POINT('',#778);
#780=EDGE_CURVE('E623',#779,#446,#777,.T.);
#781=ORIENTED_EDGE('',*,*,#780,.F.);
#782=DIRECTION('',(0.38268343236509,0.923879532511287,0.));
#783=VECTOR('',#782,1.);
#784=CARTESIAN_POINT('',(2.58311316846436,6.23618684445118,0.));
#785=LINE('',#784,#783);
#786=EDGE_CURVE('E613',#423,#779,#785,.T.);
#787=ORIENTED_EDGE('',*,*,#786,.F.);
#788=ORIENTED_EDGE('',*,*,#424,.F.);
#789=DIRECTION('',(-0.831469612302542,-0.555570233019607,0.));
#790=VECTOR('',#789,1.);
#791=CARTESIAN_POINT('',(6.25082394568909,6.25082394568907,0.));
#792=LINE('',#791,#790);
#793=CARTESIAN_POINT('',(6.25082394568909,6.25082394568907,0.));
#794=VERTEX_POINT('',#793);
#795=EDGE_CURVE('E604',#794,#419,#792,.T.);
#796=ORIENTED_EDGE('',*,*,#795,.F.);
#797=DIRECTION('',(0.707106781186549,0.707106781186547,0.));
#798=VECTOR('',#797,1.);
#799=CARTESIAN_POINT('',(4.7729707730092,4.77297077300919,0.));
#800=LINE('',#799,#798);
#801=EDGE_CURVE('E594',#396,#794,#800,.T.);
#802=ORIENTED_EDGE('',*,*,#801,.F.);
#803=ORIENTED_EDGE('',*,*,#397,.F.);
#804=DIRECTION('',(-0.980785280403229,-0.195090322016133,0.));
#805=VECTOR('',#804,1.);
#806=CARTESIAN_POINT('',(8.16709506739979,3.38292154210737,0.));
#807=LINE('',#806,#805);
#808=CARTESIAN_POINT('',(8.16709506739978,3.38292154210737,0.));
#809=VERTEX_POINT('',#808);
#810=EDGE_CURVE('E585',#809,#392,#807,.T.);
#811=ORIENTED_EDGE('',*,*,#810,.F.);
#812=DIRECTION('',(0.923879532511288,0.382683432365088,0.));
#813=VECTOR('',#812,1.);
#814=CARTESIAN_POINT('',(6.23618684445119,2.58311316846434,0.));
#815=LINE('',#814,#813);
#816=EDGE_CURVE('E575',#369,#809,#815,.T.);
#817=ORIENTED_EDGE('',*,*,#816,.F.);
#818=ORIENTED_EDGE('',*,*,#370,.F.);
#819=DIRECTION('',(-0.980785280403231,0.195090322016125,0.));
#820=VECTOR('',#819,1.);
#821=CARTESIAN_POINT('',(8.84,0.,0.));
#822=LINE('',#821,#820);
#823=CARTESIAN_POINT('',(8.84,0.,0.));
#824=VERTEX_POINT('',#823);
#825=EDGE_CURVE('E566',#824,#365,#822,.T.);
#826=ORIENTED_EDGE('',*,*,#825,.F.);
#827=DIRECTION('',(1.,0.,0.));
#828=VECTOR('',#827,1.);
#829=CARTESIAN_POINT('',(6.75,0.,0.));
#830=LINE('',#829,#828);
#831=EDGE_CURVE('E556',#342,#824,#830,.T.);
#832=ORIENTED_EDGE('',*,*,#831,.F.);
#833=ORIENTED_EDGE('',*,*,#343,.F.);
#834=DIRECTION('',(-0.831469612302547,0.5555702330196,0.));
#835=VECTOR('',#834,1.);
#836=CARTESIAN_POINT('',(8.16709506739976,-3.38292154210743,0.));
#837=LINE('',#836,#835);
#838=CARTESIAN_POINT('',(8.16709506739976,-3.38292154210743,0.));
#839=VERTEX_POINT('',#838);
#840=EDGE_CURVE('E547',#839,#338,#837,.T.);
#841=ORIENTED_EDGE('',*,*,#840,.F.);
#842=DIRECTION('',(0.923879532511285,-0.382683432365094,0.));
#843=VECTOR('',#842,1.);
#844=CARTESIAN_POINT('',(6.23618684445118,-2.58311316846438,0.));
#845=LINE('',#844,#843);
#846=EDGE_CURVE('E537',#315,#839,#845,.T.);
#847=ORIENTED_EDGE('',*,*,#846,.F.);
#848=ORIENTED_EDGE('',*,*,#316,.F.);
#849=DIRECTION('',(-0.555570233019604,0.831469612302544,0.));
#850=VECTOR('',#849,1.);
#851=CARTESIAN_POINT('',(6.25082394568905,-6.25082394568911,0.));
#852=LINE('',#851,#850);
#853=CARTESIAN_POINT('',(6.25082394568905,-6.25082394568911,0.));
#854=VERTEX_POINT('',#853);
#855=EDGE_CURVE('E528',#854,#311,#852,.T.);
#856=ORIENTED_EDGE('',*,*,#855,.F.);
#857=DIRECTION('',(0.707106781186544,-0.707106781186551,0.));
#858=VECTOR('',#857,1.);
#859=CARTESIAN_POINT('',(4.77297077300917,-4.77297077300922,0.));
#860=LINE('',#859,#858);
#861=EDGE_CURVE('E518',#288,#854,#860,.T.);
#862=ORIENTED_EDGE('',*,*,#861,.F.);
#863=ORIENTED_EDGE('',*,*,#289,.F.);
#864=DIRECTION('',(-0.195090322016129,0.98078528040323,0.));
#865=VECTOR('',#864,1.);
#866=CARTESIAN_POINT('',(3.38292154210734,-8.1670950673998,0.));
#867=LINE('',#866,#865);
#868=CARTESIAN_POINT('',(3.38292154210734,-8.1670950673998,0.));
#869=VERTEX_POINT('',#868);
#870=EDGE_CURVE('E509',#869,#284,#867,.T.);
#871=ORIENTED_EDGE('',*,*,#870,.F.);
#872=DIRECTION('',(0.382683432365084,-0.923879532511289,0.));
#873=VECTOR('',#872,1.);
#874=CARTESIAN_POINT('',(2.58311316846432,-6.2361868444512,0.));
#875=LINE('',#874,#873);
#876=EDGE_CURVE('E499',#261,#869,#875,.T.);
#877=ORIENTED_EDGE('',*,*,#876,.F.);
#878=ORIENTED_EDGE('',*,*,#262,.F.);
#879=DIRECTION('',(0.195090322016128,0.98078528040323,0.));
#880=VECTOR('',#879,1.);
#881=CARTESIAN_POINT('',(0.,-8.84,0.));
#882=LINE('',#881,#880);
#883=CARTESIAN_POINT('',(0.,-8.84,0.));
#884=VERTEX_POINT('',#883);
#885=EDGE_CURVE('E490',#884,#257,#882,.T.);
#886=ORIENTED_EDGE('',*,*,#885,.F.);
#887=DIRECTION('',(0.,-1.,0.));
#888=VECTOR('',#887,1.);
#889=CARTESIAN_POINT('',(0.,-6.75,0.));
#890=LINE('',#889,#888);
#891=EDGE_CURVE('E480',#234,#884,#890,.T.);
#892=ORIENTED_EDGE('',*,*,#891,.F.);
#893=ORIENTED_EDGE('',*,*,#235,.F.);
#894=DIRECTION('',(0.555570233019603,0.831469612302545,0.));
#895=VECTOR('',#894,1.);
#896=CARTESIAN_POINT('',(-3.38292154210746,-8.16709506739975,0.));
#897=LINE('',#896,#895);
#898=CARTESIAN_POINT('',(-3.38292154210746,-8.16709506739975,0.));
#899=VERTEX_POINT('',#898);
#900=EDGE_CURVE('E471',#899,#230,#897,.T.);
#901=ORIENTED_EDGE('',*,*,#900,.F.);
#902=DIRECTION('',(-0.382683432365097,-0.923879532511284,0.));
#903=VECTOR('',#902,1.);
#904=CARTESIAN_POINT('',(-2.58311316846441,-6.23618684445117,0.));
#905=LINE('',#904,#903);
#906=EDGE_CURVE('E461',#207,#899,#905,.T.);
#907=ORIENTED_EDGE('',*,*,#906,.F.);
#908=ORIENTED_EDGE('',*,*,#208,.F.);
#909=DIRECTION('',(0.831469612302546,0.555570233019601,0.));
#910=VECTOR('',#909,1.);
#911=CARTESIAN_POINT('',(-6.25082394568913,-6.25082394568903,0.));
#912=LINE('',#911,#910);
#913=CARTESIAN_POINT('',(-6.25082394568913,-6.25082394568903,0.));
#914=VERTEX_POINT('',#913);
#915=EDGE_CURVE('E452',#914,#203,#912,.T.);
#916=ORIENTED_EDGE('',*,*,#915,.F.);
#917=DIRECTION('',(-0.707106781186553,-0.707106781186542,0.));
#918=VECTOR('',#917,1.);
#919=CARTESIAN_POINT('',(-4.77297077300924,-4.77297077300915,0.));
#920=LINE('',#919,#918);
#921=EDGE_CURVE('E442',#180,#914,#920,.T.);
#922=ORIENTED_EDGE('',*,*,#921,.F.);
#923=ORIENTED_EDGE('',*,*,#181,.F.);
#924=DIRECTION('',(0.980785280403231,0.195090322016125,0.));
#925=VECTOR('',#924,1.);
#926=CARTESIAN_POINT('',(-8.16709506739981,-3.38292154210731,0.));
#927=LINE('',#926,#925);
#928=CARTESIAN_POINT('',(-8.16709506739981,-3.38292154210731,0.));
#929=VERTEX_POINT('',#928);
#930=EDGE_CURVE('E433',#929,#176,#927,.T.);
#931=ORIENTED_EDGE('',*,*,#930,.F.);
#932=DIRECTION('',(-0.923879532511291,-0.382683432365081,0.));
#933=VECTOR('',#932,1.);
#934=CARTESIAN_POINT('',(-6.23618684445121,-2.58311316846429,0.));
#935=LINE('',#934,#933);
#936=EDGE_CURVE('E423',#153,#929,#935,.T.);
#937=ORIENTED_EDGE('',*,*,#936,.F.);
#938=ORIENTED_EDGE('',*,*,#154,.F.);
#939=DIRECTION('',(0.98078528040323,-0.195090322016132,0.));
#940=VECTOR('',#939,1.);
#941=CARTESIAN_POINT('',(-8.84,0.,0.));
#942=LINE('',#941,#940);
#943=CARTESIAN_POINT('',(-8.84,0.,0.));
#944=VERTEX_POINT('',#943);
#945=EDGE_CURVE('E414',#944,#149,#942,.T.);
#946=ORIENTED_EDGE('',*,*,#945,.F.);
#947=DIRECTION('',(-1.,0.,0.));
#948=VECTOR('',#947,1.);
#949=CARTESIAN_POINT('',(-6.75,0.,0.));
#950=LINE('',#949,#948);
#951=EDGE_CURVE('E404',#126,#944,#950,.T.);
#952=ORIENTED_EDGE('',*,*,#951,.F.);
#953=ORIENTED_EDGE('',*,*,#127,.F.);
#954=DIRECTION('',(0.831469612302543,-0.555570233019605,0.));
#955=VECTOR('',#954,1.);
#956=CARTESIAN_POINT('',(-8.16709506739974,3.38292154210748,0.));
#957=LINE('',#956,#955);
#958=CARTESIAN_POINT('',(-8.16709506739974,3.38292154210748,0.));
#959=VERTEX_POINT('',#958);
#960=EDGE_CURVE('E395',#959,#122,#957,.T.);
#961=ORIENTED_EDGE('',*,*,#960,.F.);
#962=DIRECTION('',(-0.923879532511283,0.3826834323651,0.));
#963=VECTOR('',#962,1.);
#964=CARTESIAN_POINT('',(-6.23618684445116,2.58311316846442,0.));
#965=LINE('',#964,#963);
#966=EDGE_CURVE('E386',#99,#959,#965,.T.);
#967=ORIENTED_EDGE('',*,*,#966,.F.);
#968=ORIENTED_EDGE('',*,*,#100,.F.);
#969=DIRECTION('',(0.555570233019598,-0.831469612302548,0.));
#970=VECTOR('',#969,1.);
#971=CARTESIAN_POINT('',(-6.250823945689,6.25082394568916,0.));
#972=LINE('',#971,#970);
#973=CARTESIAN_POINT('',(-6.250823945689,6.25082394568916,0.));
#974=VERTEX_POINT('',#973);
#975=EDGE_CURVE('E378',#974,#95,#972,.T.);
#976=ORIENTED_EDGE('',*,*,#975,.F.);
#977=DIRECTION('',(-0.707106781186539,0.707106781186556,0.));
#978=VECTOR('',#977,1.);
#979=CARTESIAN_POINT('',(-4.77297077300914,4.77297077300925,0.));
#980=LINE('',#979,#978);
#981=EDGE_CURVE('E65',#72,#974,#980,.T.);
#982=ORIENTED_EDGE('',*,*,#981,.F.);
#983=ORIENTED_EDGE('',*,*,#73,.F.);
#984=DIRECTION('',(0.195090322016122,-0.980785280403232,0.));
#985=VECTOR('',#984,1.);
#986=CARTESIAN_POINT('',(-3.38292154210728,8.16709506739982,0.));
#987=LINE('',#986,#985);
#988=EDGE_CURVE('E366',#755,#68,#987,.T.);
#989=ORIENTED_EDGE('',*,*,#988,.F.);
#990=EDGE_LOOP('',(#757,#758,#766,#772,#773,#781,#787,#788,#796,#802,#803,#811,#817,#818,#826,
#832,#833,#841,#847,#848,#856,#862,#863,#871,#877,#878,#886,#892,#893,#901,#907,#908,#916,#922,
#923,#931,#937,#938,#946,#952,#953,#961,#967,#968,#976,#982,#983,#989));
#991=FACE_BOUND('',#990,.T.);
#992=ORIENTED_EDGE('',*,*,#740,.T.);
#993=EDGE_LOOP('',(#992));
#994=FACE_BOUND('',#993,.T.);
#995=ADVANCED_FACE('F775',(#991,#994),#749,.T.);
#996=CARTESIAN_POINT('',(0.,6.75,-1.));
#997=DIRECTION('',(1.,0.,0.));
#998=DIRECTION('',(0.,1.,0.));
#999=AXIS2_PLACEMENT_3D('',#996,#997,#998);
#1000=PLANE('',#999);
#1001=ORIENTED_EDGE('',*,*,#771,.T.);
#1002=DIRECTION('',(0.,0.,1.));
#1003=VECTOR('',#1002,1.);
#1004=CARTESIAN_POINT('',(0.,8.84,-1.));
#1005=LINE('',#1004,#1003);
#1006=EDGE_CURVE('E644',#701,#764,#1005,.T.);
#1007=ORIENTED_EDGE('',*,*,#1006,.F.);
#1008=ORIENTED_EDGE('',*,*,#702,.F.);
#1009=ORIENTED_EDGE('',*,*,#459,.T.);
#1010=EDGE_LOOP('',(#1001,#1007,#1008,#1009));
#1011=FACE_BOUND('',#1010,.T.);
#1012=ADVANCED_FACE('F773',(#1011),#1000,.F.);
#1013=CARTESIAN_POINT('',(0.,8.84,-1.));
#1014=DIRECTION('',(-0.980785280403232,0.195090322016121,0.));
#1015=DIRECTION('',(-0.195090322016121,-0.980785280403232,0.));
#1016=AXIS2_PLACEMENT_3D('',#1013,#1014,#1015);
#1017=PLANE('',#1016);
#1018=ORIENTED_EDGE('',*,*,#765,.T.);
#1019=ORIENTED_EDGE('',*,*,#49,.F.);
#1020=ORIENTED_EDGE('',*,*,#708,.F.);
#1021=ORIENTED_EDGE('',*,*,#1006,.T.);
#1022=EDGE_LOOP('',(#1018,#1019,#1020,#1021));
#1023=FACE_BOUND('',#1022,.T.);
#1024=ADVANCED_FACE('F779',(#1023),#1017,.F.);
#1025=CARTESIAN_POINT('',(2.58311316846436,6.23618684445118,-1.));
#1026=DIRECTION('',(0.923879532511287,-0.38268343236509,0.));
#1027=DIRECTION('',(0.38268343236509,0.923879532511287,0.));
#1028=AXIS2_PLACEMENT_3D('',#1025,#1026,#1027);
#1029=PLANE('',#1028);
#1030=ORIENTED_EDGE('',*,*,#786,.T.);
#1031=DIRECTION('',(0.,0.,1.));
#1032=VECTOR('',#1031,1.);
#1033=CARTESIAN_POINT('',(3.3829215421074,8.16709506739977,-1.));
#1034=LINE('',#1033,#1032);
#1035=EDGE_CURVE('E626',#686,#779,#1034,.T.);
#1036=ORIENTED_EDGE('',*,*,#1035,.F.);
#1037=ORIENTED_EDGE('',*,*,#687,.F.);
#1038=ORIENTED_EDGE('',*,*,#432,.T.);
#1039=EDGE_LOOP('',(#1030,#1036,#1037,#1038));
#1040=FACE_BOUND('',#1039,.T.);
#1041=ADVANCED_FACE('F806',(#1040),#1029,.F.);
#1042=CARTESIAN_POINT('',(3.3829215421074,8.16709506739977,-1.));
#1043=DIRECTION('',(-0.831469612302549,0.555570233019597,0.));
#1044=DIRECTION('',(-0.555570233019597,-0.831469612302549,0.));
#1045=AXIS2_PLACEMENT_3D('',#1042,#1043,#1044);
#1046=PLANE('',#1045);
#1047=ORIENTED_EDGE('',*,*,#780,.T.);
#1048=ORIENTED_EDGE('',*,*,#447,.F.);
#1049=ORIENTED_EDGE('',*,*,#693,.F.);
#1050=ORIENTED_EDGE('',*,*,#1035,.T.);
#1051=EDGE_LOOP('',(#1047,#1048,#1049,#1050));
#1052=FACE_BOUND('',#1051,.T.);
#1053=ADVANCED_FACE('F809',(#1052),#1046,.F.);
#1054=CARTESIAN_POINT('',(4.7729707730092,4.77297077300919,-1.));
#1055=DIRECTION('',(0.707106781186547,-0.707106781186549,0.));
#1056=DIRECTION('',(0.707106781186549,0.707106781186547,0.));
#1057=AXIS2_PLACEMENT_3D('',#1054,#1055,#1056);
#1058=PLANE('',#1057);
#1059=ORIENTED_EDGE('',*,*,#801,.T.);
#1060=DIRECTION('',(0.,0.,1.));
#1061=VECTOR('',#1060,1.);
#1062=CARTESIAN_POINT('',(6.25082394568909,6.25082394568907,-1.));
#1063=LINE('',#1062,#1061);
#1064=EDGE_CURVE('E607',#671,#794,#1063,.T.);
#1065=ORIENTED_EDGE('',*,*,#1064,.F.);
#1066=ORIENTED_EDGE('',*,*,#672,.F.);
#1067=ORIENTED_EDGE('',*,*,#405,.T.);
#1068=EDGE_LOOP('',(#1059,#1065,#1066,#1067));
#1069=FACE_BOUND('',#1068,.T.);
#1070=ADVANCED_FACE('F811',(#1069),#1058,.F.);
#1071=CARTESIAN_POINT('',(6.25082394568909,6.25082394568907,-1.));
#1072=DIRECTION('',(-0.555570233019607,0.831469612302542,0.));
#1073=DIRECTION('',(-0.831469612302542,-0.555570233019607,0.));
#1074=AXIS2_PLACEMENT_3D('',#1071,#1072,#1073);
#1075=PLANE('',#1074);
#1076=ORIENTED_EDGE('',*,*,#795,.T.);
#1077=ORIENTED_EDGE('',*,*,#420,.F.);
#1078=ORIENTED_EDGE('',*,*,#678,.F.);
#1079=ORIENTED_EDGE('',*,*,#1064,.T.);
#1080=EDGE_LOOP('',(#1076,#1077,#1078,#1079));
#1081=FACE_BOUND('',#1080,.T.);
#1082=ADVANCED_FACE('F818',(#1081),#1075,.F.);
#1083=CARTESIAN_POINT('',(6.23618684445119,2.58311316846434,-1.));
#1084=DIRECTION('',(0.382683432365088,-0.923879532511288,0.));
#1085=DIRECTION('',(0.923879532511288,0.382683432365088,0.));
#1086=AXIS2_PLACEMENT_3D('',#1083,#1084,#1085);
#1087=PLANE('',#1086);
#1088=ORIENTED_EDGE('',*,*,#816,.T.);
#1089=DIRECTION('',(0.,0.,1.));
#1090=VECTOR('',#1089,1.);
#1091=CARTESIAN_POINT('',(8.16709506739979,3.38292154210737,-1.));
#1092=LINE('',#1091,#1090);
#1093=EDGE_CURVE('E588',#656,#809,#1092,.T.);
#1094=ORIENTED_EDGE('',*,*,#1093,.F.);
#1095=ORIENTED_EDGE('',*,*,#657,.F.);
#1096=ORIENTED_EDGE('',*,*,#378,.T.);
#1097=EDGE_LOOP('',(#1088,#1094,#1095,#1096));
#1098=FACE_BOUND('',#1097,.T.);
#1099=ADVANCED_FACE('F977',(#1098),#1087,.F.);
#1100=CARTESIAN_POINT('',(8.16709506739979,3.38292154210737,-1.));
#1101=DIRECTION('',(-0.195090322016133,0.98078528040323,0.));
#1102=DIRECTION('',(-0.98078528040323,-0.195090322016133,0.));
#1103=AXIS2_PLACEMENT_3D('',#1100,#1101,#1102);
#1104=PLANE('',#1103);
#1105=ORIENTED_EDGE('',*,*,#810,.T.);
#1106=ORIENTED_EDGE('',*,*,#393,.F.);
#1107=ORIENTED_EDGE('',*,*,#663,.F.);
#1108=ORIENTED_EDGE('',*,*,#1093,.T.);
#1109=EDGE_LOOP('',(#1105,#1106,#1107,#1108));
#1110=FACE_BOUND('',#1109,.T.);
#1111=ADVANCED_FACE('F986',(#1110),#1104,.F.);
#1112=CARTESIAN_POINT('',(6.75,0.,-1.));
#1113=DIRECTION('',(0.,-1.,0.));
#1114=DIRECTION('',(1.,0.,0.));
#1115=AXIS2_PLACEMENT_3D('',#1112,#1113,#1114);
#1116=PLANE('',#1115);
#1117=ORIENTED_EDGE('',*,*,#831,.T.);
#1118=DIRECTION('',(0.,0.,1.));
#1119=VECTOR('',#1118,1.);
#1120=CARTESIAN_POINT('',(8.84,0.,-1.));
#1121=LINE('',#1120,#1119);
#1122=EDGE_CURVE('E569',#641,#824,#1121,.T.);
#1123=ORIENTED_EDGE('',*,*,#1122,.F.);
#1124=ORIENTED_EDGE('',*,*,#642,.F.);
#1125=ORIENTED_EDGE('',*,*,#351,.T.);
#1126=EDGE_LOOP('',(#1117,#1123,#1124,#1125));
#1127=FACE_BOUND('',#1126,.T.);
#1128=ADVANCED_FACE('F997',(#1127),#1116,.F.);
#1129=CARTESIAN_POINT('',(8.84,0.,-1.));
#1130=DIRECTION('',(0.195090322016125,0.980785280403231,0.));
#1131=DIRECTION('',(-0.980785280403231,0.195090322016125,0.));
#1132=AXIS2_PLACEMENT_3D('',#1129,#1130,#1131);
#1133=PLANE('',#1132);
#1134=ORIENTED_EDGE('',*,*,#825,.T.);
#1135=ORIENTED_EDGE('',*,*,#366,.F.);
#1136=ORIENTED_EDGE('',*,*,#648,.F.);
#1137=ORIENTED_EDGE('',*,*,#1122,.T.);
#1138=EDGE_LOOP('',(#1134,#1135,#1136,#1137));
#1139=FACE_BOUND('',#1138,.T.);
#1140=ADVANCED_FACE('F1008',(#1139),#1133,.F.);
#1141=CARTESIAN_POINT('',(6.23618684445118,-2.58311316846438,-1.));
#1142=DIRECTION('',(-0.382683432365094,-0.923879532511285,0.));
#1143=DIRECTION('',(0.923879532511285,-0.382683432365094,0.));
#1144=AXIS2_PLACEMENT_3D('',#1141,#1142,#1143);
#1145=PLANE('',#1144);
#1146=ORIENTED_EDGE('',*,*,#846,.T.);
#1147=DIRECTION('',(0.,0.,1.));
#1148=VECTOR('',#1147,1.);
#1149=CARTESIAN_POINT('',(8.16709506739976,-3.38292154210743,-1.));
#1150=LINE('',#1149,#1148);
#1151=EDGE_CURVE('E550',#626,#839,#1150,.T.);
#1152=ORIENTED_EDGE('',*,*,#1151,.F.);
#1153=ORIENTED_EDGE('',*,*,#627,.F.);
#1154=ORIENTED_EDGE('',*,*,#324,.T.);
#1155=EDGE_LOOP('',(#1146,#1152,#1153,#1154));
#1156=FACE_BOUND('',#1155,.T.);
#1157=ADVANCED_FACE('F1019',(#1156),#1145,.F.);
#1158=CARTESIAN_POINT('',(8.16709506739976,-3.38292154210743,-1.));
#1159=DIRECTION('',(0.5555702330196,0.831469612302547,0.));
#1160=DIRECTION('',(-0.831469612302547,0.5555702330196,0.));
#1161=AXIS2_PLACEMENT_3D('',#1158,#1159,#1160);
#1162=PLANE('',#1161);
#1163=ORIENTED_EDGE('',*,*,#840,.T.);
#1164=ORIENTED_EDGE('',*,*,#339,.F.);
#1165=ORIENTED_EDGE('',*,*,#633,.F.);
#1166=ORIENTED_EDGE('',*,*,#1151,.T.);
#1167=EDGE_LOOP('',(#1163,#1164,#1165,#1166));
#1168=FACE_BOUND('',#1167,.T.);
#1169=ADVANCED_FACE('F1030',(#1168),#1162,.F.);
#1170=CARTESIAN_POINT('',(4.77297077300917,-4.77297077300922,-1.));
#1171=DIRECTION('',(-0.707106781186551,-0.707106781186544,0.));
#1172=DIRECTION('',(0.707106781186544,-0.707106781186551,0.));
#1173=AXIS2_PLACEMENT_3D('',#1170,#1171,#1172);
#1174=PLANE('',#1173);
#1175=ORIENTED_EDGE('',*,*,#861,.T.);
#1176=DIRECTION('',(0.,0.,1.));
#1177=VECTOR('',#1176,1.);
#1178=CARTESIAN_POINT('',(6.25082394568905,-6.25082394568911,-1.));
#1179=LINE('',#1178,#1177);
#1180=EDGE_CURVE('E531',#611,#854,#1179,.T.);
#1181=ORIENTED_EDGE('',*,*,#1180,.F.);
#1182=ORIENTED_EDGE('',*,*,#612,.F.);
#1183=ORIENTED_EDGE('',*,*,#297,.T.);
#1184=EDGE_LOOP('',(#1175,#1181,#1182,#1183));
#1185=FACE_BOUND('',#1184,.T.);
#1186=ADVANCED_FACE('F1041',(#1185),#1174,.F.);
#1187=CARTESIAN_POINT('',(6.25082394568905,-6.25082394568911,-1.));
#1188=DIRECTION('',(0.831469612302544,0.555570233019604,0.));
#1189=DIRECTION('',(-0.555570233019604,0.831469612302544,0.));
#1190=AXIS2_PLACEMENT_3D('',#1187,#1188,#1189);
#1191=PLANE('',#1190);
#1192=ORIENTED_EDGE('',*,*,#855,.T.);
#1193=ORIENTED_EDGE('',*,*,#312,.F.);
#1194=ORIENTED_EDGE('',*,*,#618,.F.);
#1195=ORIENTED_EDGE('',*,*,#1180,.T.);
#1196=EDGE_LOOP('',(#1192,#1193,#1194,#1195));
#1197=FACE_BOUND('',#1196,.T.);
#1198=ADVANCED_FACE('F1052',(#1197),#1191,.F.);
#1199=CARTESIAN_POINT('',(2.58311316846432,-6.2361868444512,-1.));
#1200=DIRECTION('',(-0.923879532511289,-0.382683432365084,0.));
#1201=DIRECTION('',(0.382683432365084,-0.923879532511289,0.));
#1202=AXIS2_PLACEMENT_3D('',#1199,#1200,#1201);
#1203=PLANE('',#1202);
#1204=ORIENTED_EDGE('',*,*,#876,.T.);
#1205=DIRECTION('',(0.,0.,1.));
#1206=VECTOR('',#1205,1.);
#1207=CARTESIAN_POINT('',(3.38292154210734,-8.1670950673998,-1.));
#1208=LINE('',#1207,#1206);
#1209=EDGE_CURVE('E512',#596,#869,#1208,.T.);
#1210=ORIENTED_EDGE('',*,*,#1209,.F.);
#1211=ORIENTED_EDGE('',*,*,#597,.F.);
#1212=ORIENTED_EDGE('',*,*,#270,.T.);
#1213=EDGE_LOOP('',(#1204,#1210,#1211,#1212));
#1214=FACE_BOUND('',#1213,.T.);
#1215=ADVANCED_FACE('F1063',(#1214),#1203,.F.);
#1216=CARTESIAN_POINT('',(3.38292154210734,-8.1670950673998,-1.));
#1217=DIRECTION('',(0.98078528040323,0.195090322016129,0.));
#1218=DIRECTION('',(-0.195090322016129,0.98078528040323,0.));
#1219=AXIS2_PLACEMENT_3D('',#1216,#1217,#1218);
#1220=PLANE('',#1219);
#1221=ORIENTED_EDGE('',*,*,#870,.T.);
#1222=ORIENTED_EDGE('',*,*,#285,.F.);
#1223=ORIENTED_EDGE('',*,*,#603,.F.);
#1224=ORIENTED_EDGE('',*,*,#1209,.T.);
#1225=EDGE_LOOP('',(#1221,#1222,#1223,#1224));
#1226=FACE_BOUND('',#1225,.T.);
#1227=ADVANCED_FACE('F1074',(#1226),#1220,.F.);
#1228=CARTESIAN_POINT('',(0.,-6.75,-1.));
#1229=DIRECTION('',(-1.,0.,0.));
#1230=DIRECTION('',(0.,-1.,0.));
#1231=AXIS2_PLACEMENT_3D('',#1228,#1229,#1230);
#1232=PLANE('',#1231);
#1233=ORIENTED_EDGE('',*,*,#891,.T.);
#1234=DIRECTION('',(0.,0.,1.));
#1235=VECTOR('',#1234,1.);
#1236=CARTESIAN_POINT('',(0.,-8.84,-1.));
#1237=LINE('',#1236,#1235);
#1238=EDGE_CURVE('E493',#581,#884,#1237,.T.);
#1239=ORIENTED_EDGE('',*,*,#1238,.F.);
#1240=ORIENTED_EDGE('',*,*,#582,.F.);
#1241=ORIENTED_EDGE('',*,*,#243,.T.);
#1242=EDGE_LOOP('',(#1233,#1239,#1240,#1241));
#1243=FACE_BOUND('',#1242,.T.);
#1244=ADVANCED_FACE('F1085',(#1243),#1232,.F.);
#1245=CARTESIAN_POINT('',(0.,-8.84,-1.));
#1246=DIRECTION('',(0.98078528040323,-0.195090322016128,0.));
#1247=DIRECTION('',(0.195090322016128,0.980785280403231,0.));
#1248=AXIS2_PLACEMENT_3D('',#1245,#1246,#1247);
#1249=PLANE('',#1248);
#1250=ORIENTED_EDGE('',*,*,#885,.T.);
#1251=ORIENTED_EDGE('',*,*,#258,.F.);
#1252=ORIENTED_EDGE('',*,*,#588,.F.);
#1253=ORIENTED_EDGE('',*,*,#1238,.T.);
#1254=EDGE_LOOP('',(#1250,#1251,#1252,#1253));
#1255=FACE_BOUND('',#1254,.T.);
#1256=ADVANCED_FACE('F1096',(#1255),#1249,.F.);
#1257=CARTESIAN_POINT('',(-2.58311316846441,-6.23618684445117,-1.));
#1258=DIRECTION('',(-0.923879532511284,0.382683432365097,0.));
#1259=DIRECTION('',(-0.382683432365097,-0.923879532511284,0.));
#1260=AXIS2_PLACEMENT_3D('',#1257,#1258,#1259);
#1261=PLANE('',#1260);
#1262=ORIENTED_EDGE('',*,*,#906,.T.);
#1263=DIRECTION('',(0.,0.,1.));
#1264=VECTOR('',#1263,1.);
#1265=CARTESIAN_POINT('',(-3.38292154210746,-8.16709506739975,-1.));
#1266=LINE('',#1265,#1264);
#1267=EDGE_CURVE('E474',#566,#899,#1266,.T.);
#1268=ORIENTED_EDGE('',*,*,#1267,.F.);
#1269=ORIENTED_EDGE('',*,*,#567,.F.);
#1270=ORIENTED_EDGE('',*,*,#216,.T.);
#1271=EDGE_LOOP('',(#1262,#1268,#1269,#1270));
#1272=FACE_BOUND('',#1271,.T.);
#1273=ADVANCED_FACE('F1107',(#1272),#1261,.F.);
#1274=CARTESIAN_POINT('',(-3.38292154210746,-8.16709506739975,-1.));
#1275=DIRECTION('',(0.831469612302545,-0.555570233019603,0.));
#1276=DIRECTION('',(0.555570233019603,0.831469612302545,0.));
#1277=AXIS2_PLACEMENT_3D('',#1274,#1275,#1276);
#1278=PLANE('',#1277);
#1279=ORIENTED_EDGE('',*,*,#900,.T.);
#1280=ORIENTED_EDGE('',*,*,#231,.F.);
#1281=ORIENTED_EDGE('',*,*,#573,.F.);
#1282=ORIENTED_EDGE('',*,*,#1267,.T.);
#1283=EDGE_LOOP('',(#1279,#1280,#1281,#1282));
#1284=FACE_BOUND('',#1283,.T.);
#1285=ADVANCED_FACE('F1118',(#1284),#1278,.F.);
#1286=CARTESIAN_POINT('',(-4.77297077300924,-4.77297077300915,-1.));
#1287=DIRECTION('',(-0.707106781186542,0.707106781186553,0.));
#1288=DIRECTION('',(-0.707106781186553,-0.707106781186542,0.));
#1289=AXIS2_PLACEMENT_3D('',#1286,#1287,#1288);
#1290=PLANE('',#1289);
#1291=ORIENTED_EDGE('',*,*,#921,.T.);
#1292=DIRECTION('',(0.,0.,1.));
#1293=VECTOR('',#1292,1.);
#1294=CARTESIAN_POINT('',(-6.25082394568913,-6.25082394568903,-1.));
#1295=LINE('',#1294,#1293);
#1296=EDGE_CURVE('E455',#551,#914,#1295,.T.);
#1297=ORIENTED_EDGE('',*,*,#1296,.F.);
#1298=ORIENTED_EDGE('',*,*,#552,.F.);
#1299=ORIENTED_EDGE('',*,*,#189,.T.);
#1300=EDGE_LOOP('',(#1291,#1297,#1298,#1299));
#1301=FACE_BOUND('',#1300,.T.);
#1302=ADVANCED_FACE('F1129',(#1301),#1290,.F.);
#1303=CARTESIAN_POINT('',(-6.25082394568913,-6.25082394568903,-1.));
#1304=DIRECTION('',(0.555570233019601,-0.831469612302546,0.));
#1305=DIRECTION('',(0.831469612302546,0.555570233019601,0.));
#1306=AXIS2_PLACEMENT_3D('',#1303,#1304,#1305);
#1307=PLANE('',#1306);
#1308=ORIENTED_EDGE('',*,*,#915,.T.);
#1309=ORIENTED_EDGE('',*,*,#204,.F.);
#1310=ORIENTED_EDGE('',*,*,#558,.F.);
#1311=ORIENTED_EDGE('',*,*,#1296,.T.);
#1312=EDGE_LOOP('',(#1308,#1309,#1310,#1311));
#1313=FACE_BOUND('',#1312,.T.);
#1314=ADVANCED_FACE('F1140',(#1313),#1307,.F.);
#1315=CARTESIAN_POINT('',(-6.23618684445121,-2.58311316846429,-1.));
#1316=DIRECTION('',(-0.382683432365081,0.923879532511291,0.));
#1317=DIRECTION('',(-0.923879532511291,-0.382683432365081,0.));
#1318=AXIS2_PLACEMENT_3D('',#1315,#1316,#1317);
#1319=PLANE('',#1318);
#1320=ORIENTED_EDGE('',*,*,#936,.T.);
#1321=DIRECTION('',(0.,0.,1.));
#1322=VECTOR('',#1321,1.);
#1323=CARTESIAN_POINT('',(-8.16709506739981,-3.38292154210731,-1.));
#1324=LINE('',#1323,#1322);
#1325=EDGE_CURVE('E436',#536,#929,#1324,.T.);
#1326=ORIENTED_EDGE('',*,*,#1325,.F.);
#1327=ORIENTED_EDGE('',*,*,#537,.F.);
#1328=ORIENTED_EDGE('',*,*,#162,.T.);
#1329=EDGE_LOOP('',(#1320,#1326,#1327,#1328));
#1330=FACE_BOUND('',#1329,.T.);
#1331=ADVANCED_FACE('F1151',(#1330),#1319,.F.);
#1332=CARTESIAN_POINT('',(-8.16709506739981,-3.38292154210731,-1.));
#1333=DIRECTION('',(0.195090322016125,-0.980785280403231,0.));
#1334=DIRECTION('',(0.980785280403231,0.195090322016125,0.));
#1335=AXIS2_PLACEMENT_3D('',#1332,#1333,#1334);
#1336=PLANE('',#1335);
#1337=ORIENTED_EDGE('',*,*,#930,.T.);
#1338=ORIENTED_EDGE('',*,*,#177,.F.);
#1339=ORIENTED_EDGE('',*,*,#543,.F.);
#1340=ORIENTED_EDGE('',*,*,#1325,.T.);
#1341=EDGE_LOOP('',(#1337,#1338,#1339,#1340));
#1342=FACE_BOUND('',#1341,.T.);
#1343=ADVANCED_FACE('F1162',(#1342),#1336,.F.);
#1344=CARTESIAN_POINT('',(-6.75,0.,-1.));
#1345=DIRECTION('',(0.,1.,0.));
#1346=DIRECTION('',(-1.,0.,0.));
#1347=AXIS2_PLACEMENT_3D('',#1344,#1345,#1346);
#1348=PLANE('',#1347);
#1349=ORIENTED_EDGE('',*,*,#951,.T.);
#1350=DIRECTION('',(0.,0.,1.));
#1351=VECTOR('',#1350,1.);
#1352=CARTESIAN_POINT('',(-8.84,0.,-1.));
#1353=LINE('',#1352,#1351);
#1354=EDGE_CURVE('E417',#521,#944,#1353,.T.);
#1355=ORIENTED_EDGE('',*,*,#1354,.F.);
#1356=ORIENTED_EDGE('',*,*,#522,.F.);
#1357=ORIENTED_EDGE('',*,*,#135,.T.);
#1358=EDGE_LOOP('',(#1349,#1355,#1356,#1357));
#1359=FACE_BOUND('',#1358,.T.);
#1360=ADVANCED_FACE('F1173',(#1359),#1348,.F.);
#1361=CARTESIAN_POINT('',(-8.84,0.,-1.));
#1362=DIRECTION('',(-0.195090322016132,-0.98078528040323,0.));
#1363=DIRECTION('',(0.98078528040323,-0.195090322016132,0.));
#1364=AXIS2_PLACEMENT_3D('',#1361,#1362,#1363);
#1365=PLANE('',#1364);
#1366=ORIENTED_EDGE('',*,*,#945,.T.);
#1367=ORIENTED_EDGE('',*,*,#150,.F.);
#1368=ORIENTED_EDGE('',*,*,#528,.F.);
#1369=ORIENTED_EDGE('',*,*,#1354,.T.);
#1370=EDGE_LOOP('',(#1366,#1367,#1368,#1369));
#1371=FACE_BOUND('',#1370,.T.);
#1372=ADVANCED_FACE('F1184',(#1371),#1365,.F.);
#1373=CARTESIAN_POINT('',(-6.23618684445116,2.58311316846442,-1.));
#1374=DIRECTION('',(0.3826834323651,0.923879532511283,0.));
#1375=DIRECTION('',(-0.923879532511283,0.3826834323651,0.));
#1376=AXIS2_PLACEMENT_3D('',#1373,#1374,#1375);
#1377=PLANE('',#1376);
#1378=ORIENTED_EDGE('',*,*,#966,.T.);
#1379=DIRECTION('',(0.,0.,1.));
#1380=VECTOR('',#1379,1.);
#1381=CARTESIAN_POINT('',(-8.16709506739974,3.38292154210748,-1.));
#1382=LINE('',#1381,#1380);
#1383=EDGE_CURVE('E398',#506,#959,#1382,.T.);
#1384=ORIENTED_EDGE('',*,*,#1383,.F.);
#1385=ORIENTED_EDGE('',*,*,#507,.F.);
#1386=ORIENTED_EDGE('',*,*,#108,.T.);
#1387=EDGE_LOOP('',(#1378,#1384,#1385,#1386));
#1388=FACE_BOUND('',#1387,.T.);
#1389=ADVANCED_FACE('F1195',(#1388),#1377,.F.);
#1390=CARTESIAN_POINT('',(-8.16709506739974,3.38292154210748,-1.));
#1391=DIRECTION('',(-0.555570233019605,-0.831469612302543,0.));
#1392=DIRECTION('',(0.831469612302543,-0.555570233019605,0.));
#1393=AXIS2_PLACEMENT_3D('',#1390,#1391,#1392);
#1394=PLANE('',#1393);
#1395=ORIENTED_EDGE('',*,*,#960,.T.);
#1396=ORIENTED_EDGE('',*,*,#123,.F.);
#1397=ORIENTED_EDGE('',*,*,#513,.F.);
#1398=ORIENTED_EDGE('',*,*,#1383,.T.);
#1399=EDGE_LOOP('',(#1395,#1396,#1397,#1398));
#1400=FACE_BOUND('',#1399,.T.);
#1401=ADVANCED_FACE('F1206',(#1400),#1394,.F.);
#1402=CARTESIAN_POINT('',(-4.77297077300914,4.77297077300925,-1.));
#1403=DIRECTION('',(0.707106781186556,0.707106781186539,0.));
#1404=DIRECTION('',(-0.707106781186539,0.707106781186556,0.));
#1405=AXIS2_PLACEMENT_3D('',#1402,#1403,#1404);
#1406=PLANE('',#1405);
#1407=ORIENTED_EDGE('',*,*,#981,.T.);
#1408=DIRECTION('',(0.,0.,1.));
#1409=VECTOR('',#1408,1.);
#1410=CARTESIAN_POINT('',(-6.250823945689,6.25082394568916,-1.));
#1411=LINE('',#1410,#1409);
#1412=EDGE_CURVE('E381',#491,#974,#1411,.T.);
#1413=ORIENTED_EDGE('',*,*,#1412,.F.);
#1414=ORIENTED_EDGE('',*,*,#492,.F.);
#1415=ORIENTED_EDGE('',*,*,#81,.T.);
#1416=EDGE_LOOP('',(#1407,#1413,#1414,#1415));
#1417=FACE_BOUND('',#1416,.T.);
#1418=ADVANCED_FACE('F710',(#1417),#1406,.F.);
#1419=CARTESIAN_POINT('',(-6.250823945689,6.25082394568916,-1.));
#1420=DIRECTION('',(-0.831469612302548,-0.555570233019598,0.));
#1421=DIRECTION('',(0.555570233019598,-0.831469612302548,0.));
#1422=AXIS2_PLACEMENT_3D('',#1419,#1420,#1421);
#1423=PLANE('',#1422);
#1424=ORIENTED_EDGE('',*,*,#975,.T.);
#1425=ORIENTED_EDGE('',*,*,#96,.F.);
#1426=ORIENTED_EDGE('',*,*,#498,.F.);
#1427=ORIENTED_EDGE('',*,*,#1412,.T.);
#1428=EDGE_LOOP('',(#1424,#1425,#1426,#1427));
#1429=FACE_BOUND('',#1428,.T.);
#1430=ADVANCED_FACE('F1227',(#1429),#1423,.F.);
#1431=CARTESIAN_POINT('',(-2.58311316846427,6.23618684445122,-1.));
#1432=DIRECTION('',(0.923879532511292,0.382683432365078,0.));
#1433=DIRECTION('',(-0.382683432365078,0.923879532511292,0.));
#1434=AXIS2_PLACEMENT_3D('',#1431,#1432,#1433);
#1435=PLANE('',#1434);
#1436=ORIENTED_EDGE('',*,*,#756,.T.);
#1437=DIRECTION('',(0.,0.,1.));
#1438=VECTOR('',#1437,1.);
#1439=CARTESIAN_POINT('',(-3.38292154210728,8.16709506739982,-1.));
#1440=LINE('',#1439,#1438);
#1441=EDGE_CURVE('E345',#476,#755,#1440,.T.);
#1442=ORIENTED_EDGE('',*,*,#1441,.F.);
#1443=ORIENTED_EDGE('',*,*,#477,.F.);
#1444=ORIENTED_EDGE('',*,*,#32,.T.);
#1445=EDGE_LOOP('',(#1436,#1442,#1443,#1444));
#1446=FACE_BOUND('',#1445,.T.);
#1447=ADVANCED_FACE('F347',(#1446),#1435,.F.);
#1448=CARTESIAN_POINT('',(-3.38292154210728,8.16709506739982,-1.));
#1449=DIRECTION('',(-0.980785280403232,-0.195090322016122,0.));
#1450=DIRECTION('',(0.195090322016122,-0.980785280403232,0.));
#1451=AXIS2_PLACEMENT_3D('',#1448,#1449,#1450);
#1452=PLANE('',#1451);
#1453=ORIENTED_EDGE('',*,*,#988,.T.);
#1454=ORIENTED_EDGE('',*,*,#69,.F.);
#1455=ORIENTED_EDGE('',*,*,#483,.F.);
#1456=ORIENTED_EDGE('',*,*,#1441,.T.);
#1457=EDGE_LOOP('',(#1453,#1454,#1455,#1456));
#1458=FACE_BOUND('',#1457,.T.);
#1459=ADVANCED_FACE('F357',(#1458),#1452,.F.);
#1460=CLOSED_SHELL('',(#60,#87,#114,#141,#168,#195,#222,#249,#276,#303,#330,#357,#384,#411,#438,
#465,#724,#744,#995,#1012,#1024,#1041,#1053,#1070,#1082,#1099,#1111,#1128,#1140,#1157,#1169,
#1186,#1198,#1215,#1227,#1244,#1256,#1273,#1285,#1302,#1314,#1331,#1343,#1360,#1372,#1389,#1401,
#1418,#1430,#1447,#1459));
#1461=MANIFOLD_SOLID_BREP('B2',#1460);
#1462=ADVANCED_BREP_SHAPE_REPRESENTATION('',(#18,#1461),#14);
#1463=SHAPE_DEFINITION_REPRESENTATION(#9,#1462);
ENDSEC;
END-ISO-10303-21;
